VERSION 5.8 ;
BUSBITCHARS "[]" ;
DIVIDERCHAR "/" ;

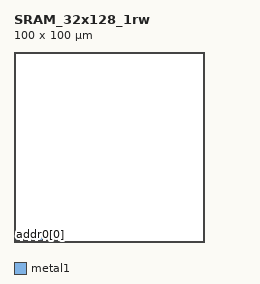
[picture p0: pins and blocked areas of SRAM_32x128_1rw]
MACRO SRAM_32x128_1rw
  CLASS BLOCK ;
  ORIGIN 0 0 ;
  FOREIGN SRAM_32x128_1rw ;
  SIZE 100 BY 100 ;

  PIN clk0
    DIRECTION INPUT ;
    USE SIGNAL ;
    PORT
      LAYER metal1 ;
      RECT 1 1 3 3 ;
    END
  END clk0

  PIN csb0
    DIRECTION INPUT ;
    USE SIGNAL ;
    PORT
      LAYER metal1 ;
      RECT 5 1 7 3 ;
    END
  END csb0

  PIN web0
    DIRECTION INPUT ;
    USE SIGNAL ;
    PORT
      LAYER metal1 ;
      RECT 9 1 11 3 ;
    END
  END web0

  PIN addr0[0]
    DIRECTION INPUT ;
    USE SIGNAL ;
    PORT
      LAYER metal1 ;
      RECT 13 1 15 3 ;
    END
  END addr0[0]

  PIN din0[0]
    DIRECTION INPUT ;
    USE SIGNAL ;
    PORT
      LAYER metal1 ;
      RECT 17 1 19 3 ;
    END
  END din0[0]

  PIN dout0[0]
    DIRECTION OUTPUT ;
    USE SIGNAL ;
    PORT
      LAYER metal1 ;
      RECT 21 1 23 3 ;
    END
  END dout0[0]

END SRAM_32x128_1rw
